VERSION 5.7 ;
  NOWIREEXTENSIONATPIN ON ;
  DIVIDERCHAR "/" ;
  BUSBITCHARS "[]" ;
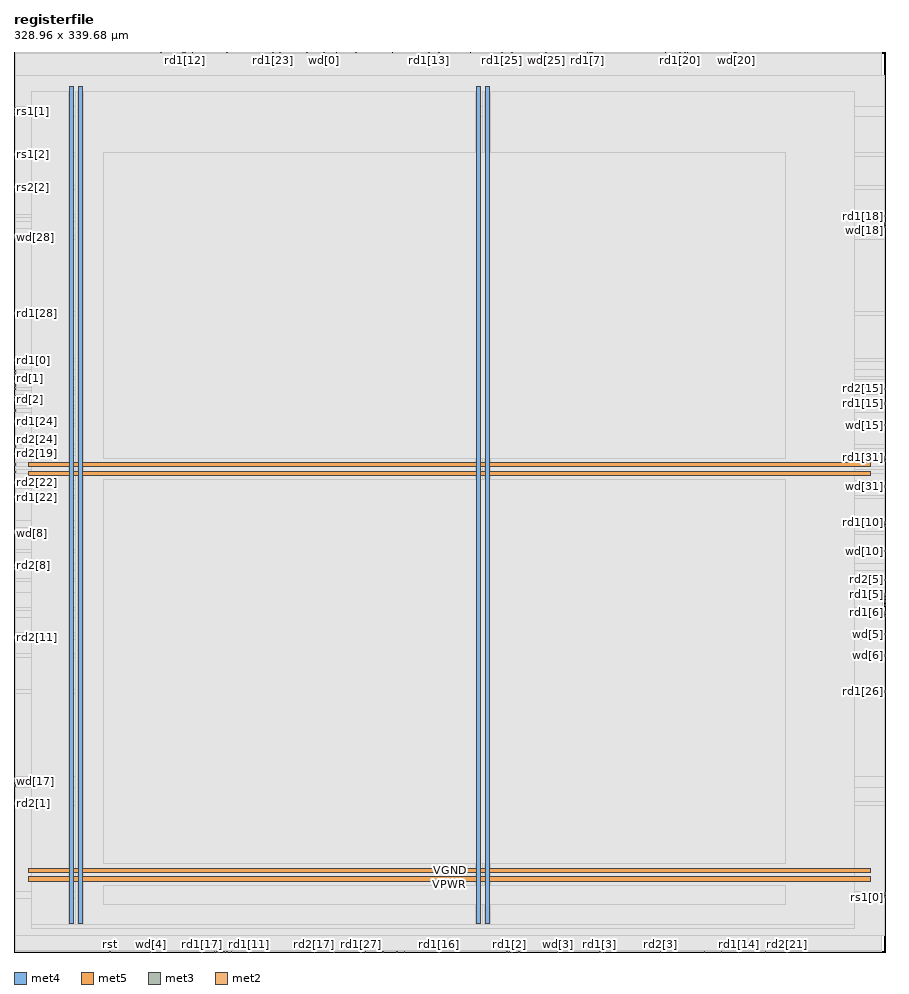
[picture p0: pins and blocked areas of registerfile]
MACRO registerfile
  CLASS BLOCK ;
  FOREIGN registerfile ;
  ORIGIN 0.000 0.000 ;
  SIZE 328.960 BY 339.680 ;
  PIN VGND
    DIRECTION INOUT ;
    USE GROUND ;
    PORT
      LAYER met4 ;
        RECT 24.340 10.640 25.940 326.640 ;
    END
    PORT
      LAYER met4 ;
        RECT 177.940 10.640 179.540 326.640 ;
    END
    PORT
      LAYER met5 ;
        RECT 5.520 30.030 323.380 31.630 ;
    END
    PORT
      LAYER met5 ;
        RECT 5.520 183.210 323.380 184.810 ;
    END
  END VGND
  PIN VPWR
    DIRECTION INOUT ;
    USE POWER ;
    PORT
      LAYER met4 ;
        RECT 21.040 10.640 22.640 326.640 ;
    END
    PORT
      LAYER met4 ;
        RECT 174.640 10.640 176.240 326.640 ;
    END
    PORT
      LAYER met5 ;
        RECT 5.520 26.730 323.380 28.330 ;
    END
    PORT
      LAYER met5 ;
        RECT 5.520 179.910 323.380 181.510 ;
    END
  END VPWR
  PIN clk
    DIRECTION INPUT ;
    USE SIGNAL ;
    ANTENNAGATEAREA 0.852000 ;
    PORT
      LAYER met3 ;
        RECT 0.000 318.280 0.600 318.880 ;
    END
  END clk
  PIN rd1[0]
    DIRECTION OUTPUT ;
    USE SIGNAL ;
    ANTENNADIFFAREA 0.383400 ;
    PORT
      LAYER met3 ;
        RECT 0.000 223.080 0.600 223.680 ;
    END
  END rd1[0]
  PIN rd1[10]
    DIRECTION OUTPUT ;
    USE SIGNAL ;
    ANTENNAGATEAREA 0.126000 ;
    ANTENNADIFFAREA 0.429000 ;
    PORT
      LAYER met3 ;
        RECT 328.360 161.880 328.960 162.480 ;
    END
  END rd1[10]
  PIN rd1[11]
    DIRECTION OUTPUT ;
    USE SIGNAL ;
    ANTENNAGATEAREA 0.126000 ;
    ANTENNADIFFAREA 0.429000 ;
    PORT
      LAYER met2 ;
        RECT 88.410 0.000 88.690 0.280 ;
    END
  END rd1[11]
  PIN rd1[12]
    DIRECTION OUTPUT ;
    USE SIGNAL ;
    ANTENNADIFFAREA 0.383400 ;
    PORT
      LAYER met2 ;
        RECT 64.490 339.400 64.770 339.680 ;
    END
  END rd1[12]
  PIN rd1[13]
    DIRECTION OUTPUT ;
    USE SIGNAL ;
    ANTENNADIFFAREA 0.429000 ;
    PORT
      LAYER met2 ;
        RECT 156.490 339.400 156.770 339.680 ;
    END
  END rd1[13]
  PIN rd1[14]
    DIRECTION OUTPUT ;
    USE SIGNAL ;
    ANTENNADIFFAREA 0.383400 ;
    PORT
      LAYER met2 ;
        RECT 273.330 0.000 273.610 0.280 ;
    END
  END rd1[14]
  PIN rd1[15]
    DIRECTION OUTPUT ;
    USE SIGNAL ;
    ANTENNAGATEAREA 0.126000 ;
    ANTENNADIFFAREA 0.429000 ;
    PORT
      LAYER met3 ;
        RECT 328.360 206.760 328.960 207.360 ;
    END
  END rd1[15]
  PIN rd1[16]
    DIRECTION OUTPUT ;
    USE SIGNAL ;
    ANTENNAGATEAREA 0.126000 ;
    ANTENNADIFFAREA 0.429000 ;
    PORT
      LAYER met2 ;
        RECT 160.170 0.000 160.450 0.280 ;
    END
  END rd1[16]
  PIN rd1[17]
    DIRECTION OUTPUT ;
    USE SIGNAL ;
    ANTENNAGATEAREA 0.126000 ;
    ANTENNADIFFAREA 0.429000 ;
    PORT
      LAYER met2 ;
        RECT 70.930 0.000 71.210 0.280 ;
    END
  END rd1[17]
  PIN rd1[18]
    DIRECTION OUTPUT ;
    USE SIGNAL ;
    ANTENNADIFFAREA 0.383400 ;
    PORT
      LAYER met3 ;
        RECT 328.360 277.480 328.960 278.080 ;
    END
  END rd1[18]
  PIN rd1[19]
    DIRECTION OUTPUT ;
    USE SIGNAL ;
    ANTENNADIFFAREA 0.383400 ;
    PORT
      LAYER met3 ;
        RECT 0.000 180.920 0.600 181.520 ;
    END
  END rd1[19]
  PIN rd1[1]
    DIRECTION OUTPUT ;
    USE SIGNAL ;
    ANTENNAGATEAREA 0.126000 ;
    ANTENNADIFFAREA 0.429000 ;
    PORT
      LAYER met2 ;
        RECT 76.450 0.000 76.730 0.280 ;
    END
  END rd1[1]
  PIN rd1[20]
    DIRECTION OUTPUT ;
    USE SIGNAL ;
    ANTENNADIFFAREA 0.383400 ;
    PORT
      LAYER met2 ;
        RECT 251.250 339.400 251.530 339.680 ;
    END
  END rd1[20]
  PIN rd1[21]
    DIRECTION OUTPUT ;
    USE SIGNAL ;
    ANTENNADIFFAREA 0.383400 ;
    PORT
      LAYER met2 ;
        RECT 283.450 0.000 283.730 0.280 ;
    END
  END rd1[21]
  PIN rd1[22]
    DIRECTION OUTPUT ;
    USE SIGNAL ;
    ANTENNADIFFAREA 0.702900 ;
    PORT
      LAYER met3 ;
        RECT 0.000 171.400 0.600 172.000 ;
    END
  END rd1[22]
  PIN rd1[23]
    DIRECTION OUTPUT ;
    USE SIGNAL ;
    ANTENNADIFFAREA 0.383400 ;
    PORT
      LAYER met2 ;
        RECT 97.610 339.400 97.890 339.680 ;
    END
  END rd1[23]
  PIN rd1[24]
    DIRECTION OUTPUT ;
    USE SIGNAL ;
    ANTENNADIFFAREA 0.383400 ;
    PORT
      LAYER met3 ;
        RECT 0.000 199.960 0.600 200.560 ;
    END
  END rd1[24]
  PIN rd1[25]
    DIRECTION OUTPUT ;
    USE SIGNAL ;
    ANTENNADIFFAREA 0.795200 ;
    PORT
      LAYER met2 ;
        RECT 184.090 339.400 184.370 339.680 ;
    END
  END rd1[25]
  PIN rd1[26]
    DIRECTION OUTPUT ;
    USE SIGNAL ;
    ANTENNAGATEAREA 0.126000 ;
    ANTENNADIFFAREA 0.429000 ;
    PORT
      LAYER met3 ;
        RECT 328.360 97.960 328.960 98.560 ;
    END
  END rd1[26]
  PIN rd1[27]
    DIRECTION OUTPUT ;
    USE SIGNAL ;
    ANTENNAGATEAREA 0.126000 ;
    ANTENNADIFFAREA 0.429000 ;
    PORT
      LAYER met2 ;
        RECT 130.730 0.000 131.010 0.280 ;
    END
  END rd1[27]
  PIN rd1[28]
    DIRECTION OUTPUT ;
    USE SIGNAL ;
    ANTENNADIFFAREA 0.383400 ;
    PORT
      LAYER met3 ;
        RECT 0.000 240.760 0.600 241.360 ;
    END
  END rd1[28]
  PIN rd1[29]
    DIRECTION OUTPUT ;
    USE SIGNAL ;
    ANTENNAGATEAREA 0.126000 ;
    ANTENNADIFFAREA 0.429000 ;
    PORT
      LAYER met2 ;
        RECT 144.530 0.000 144.810 0.280 ;
    END
  END rd1[29]
  PIN rd1[2]
    DIRECTION OUTPUT ;
    USE SIGNAL ;
    ANTENNADIFFAREA 0.891000 ;
    PORT
      LAYER met2 ;
        RECT 186.850 0.000 187.130 0.280 ;
    END
  END rd1[2]
  PIN rd1[30]
    DIRECTION OUTPUT ;
    USE SIGNAL ;
    ANTENNADIFFAREA 0.383400 ;
    PORT
      LAYER met2 ;
        RECT 128.890 339.400 129.170 339.680 ;
    END
  END rd1[30]
  PIN rd1[31]
    DIRECTION OUTPUT ;
    USE SIGNAL ;
    ANTENNAGATEAREA 0.126000 ;
    ANTENNADIFFAREA 0.429000 ;
    PORT
      LAYER met3 ;
        RECT 328.360 186.360 328.960 186.960 ;
    END
  END rd1[31]
  PIN rd1[3]
    DIRECTION OUTPUT ;
    USE SIGNAL ;
    ANTENNADIFFAREA 0.383400 ;
    PORT
      LAYER met2 ;
        RECT 220.890 0.000 221.170 0.280 ;
    END
  END rd1[3]
  PIN rd1[4]
    DIRECTION OUTPUT ;
    USE SIGNAL ;
    ANTENNADIFFAREA 0.795200 ;
    PORT
      LAYER met2 ;
        RECT 79.210 0.000 79.490 0.280 ;
    END
  END rd1[4]
  PIN rd1[5]
    DIRECTION OUTPUT ;
    USE SIGNAL ;
    ANTENNADIFFAREA 0.429000 ;
    PORT
      LAYER met3 ;
        RECT 328.360 134.680 328.960 135.280 ;
    END
  END rd1[5]
  PIN rd1[6]
    DIRECTION OUTPUT ;
    USE SIGNAL ;
    ANTENNADIFFAREA 0.383400 ;
    PORT
      LAYER met3 ;
        RECT 328.360 127.880 328.960 128.480 ;
    END
  END rd1[6]
  PIN rd1[7]
    DIRECTION OUTPUT ;
    USE SIGNAL ;
    ANTENNADIFFAREA 0.383400 ;
    PORT
      LAYER met2 ;
        RECT 216.290 339.400 216.570 339.680 ;
    END
  END rd1[7]
  PIN rd1[8]
    DIRECTION OUTPUT ;
    USE SIGNAL ;
    ANTENNAGATEAREA 0.126000 ;
    ANTENNADIFFAREA 0.429000 ;
    PORT
      LAYER met3 ;
        RECT 0.000 144.200 0.600 144.800 ;
    END
  END rd1[8]
  PIN rd1[9]
    DIRECTION OUTPUT ;
    USE SIGNAL ;
    ANTENNADIFFAREA 0.383400 ;
    PORT
      LAYER met2 ;
        RECT 253.090 339.400 253.370 339.680 ;
    END
  END rd1[9]
  PIN rd2[0]
    DIRECTION OUTPUT ;
    USE SIGNAL ;
    ANTENNADIFFAREA 0.383400 ;
    PORT
      LAYER met2 ;
        RECT 67.250 339.400 67.530 339.680 ;
    END
  END rd2[0]
  PIN rd2[10]
    DIRECTION OUTPUT ;
    USE SIGNAL ;
    ANTENNADIFFAREA 0.383400 ;
    PORT
      LAYER met3 ;
        RECT 328.360 160.520 328.960 161.120 ;
    END
  END rd2[10]
  PIN rd2[11]
    DIRECTION OUTPUT ;
    USE SIGNAL ;
    ANTENNADIFFAREA 0.383400 ;
    PORT
      LAYER met3 ;
        RECT 0.000 118.360 0.600 118.960 ;
    END
  END rd2[11]
  PIN rd2[12]
    DIRECTION OUTPUT ;
    USE SIGNAL ;
    ANTENNADIFFAREA 0.383400 ;
    PORT
      LAYER met2 ;
        RECT 55.290 339.400 55.570 339.680 ;
    END
  END rd2[12]
  PIN rd2[13]
    DIRECTION OUTPUT ;
    USE SIGNAL ;
    ANTENNAGATEAREA 0.126000 ;
    ANTENNADIFFAREA 0.429000 ;
    PORT
      LAYER met2 ;
        RECT 160.170 339.400 160.450 339.680 ;
    END
  END rd2[13]
  PIN rd2[14]
    DIRECTION OUTPUT ;
    USE SIGNAL ;
    ANTENNADIFFAREA 0.383400 ;
    PORT
      LAYER met2 ;
        RECT 266.890 0.000 267.170 0.280 ;
    END
  END rd2[14]
  PIN rd2[15]
    DIRECTION OUTPUT ;
    USE SIGNAL ;
    ANTENNAGATEAREA 0.126000 ;
    ANTENNADIFFAREA 0.429000 ;
    PORT
      LAYER met3 ;
        RECT 328.360 212.200 328.960 212.800 ;
    END
  END rd2[15]
  PIN rd2[16]
    DIRECTION OUTPUT ;
    USE SIGNAL ;
    ANTENNAGATEAREA 0.126000 ;
    ANTENNADIFFAREA 0.429000 ;
    PORT
      LAYER met3 ;
        RECT 328.360 131.960 328.960 132.560 ;
    END
  END rd2[16]
  PIN rd2[17]
    DIRECTION OUTPUT ;
    USE SIGNAL ;
    ANTENNADIFFAREA 0.445500 ;
    PORT
      LAYER met2 ;
        RECT 113.250 0.000 113.530 0.280 ;
    END
  END rd2[17]
  PIN rd2[18]
    DIRECTION OUTPUT ;
    USE SIGNAL ;
    ANTENNADIFFAREA 0.795200 ;
    PORT
      LAYER met2 ;
        RECT 218.130 339.400 218.410 339.680 ;
    END
  END rd2[18]
  PIN rd2[19]
    DIRECTION OUTPUT ;
    USE SIGNAL ;
    ANTENNADIFFAREA 0.383400 ;
    PORT
      LAYER met3 ;
        RECT 0.000 187.720 0.600 188.320 ;
    END
  END rd2[19]
  PIN rd2[1]
    DIRECTION OUTPUT ;
    USE SIGNAL ;
    ANTENNADIFFAREA 0.383400 ;
    PORT
      LAYER met3 ;
        RECT 0.000 55.800 0.600 56.400 ;
    END
  END rd2[1]
  PIN rd2[20]
    DIRECTION OUTPUT ;
    USE SIGNAL ;
    ANTENNAGATEAREA 0.126000 ;
    ANTENNADIFFAREA 0.429000 ;
    PORT
      LAYER met2 ;
        RECT 245.730 339.400 246.010 339.680 ;
    END
  END rd2[20]
  PIN rd2[21]
    DIRECTION OUTPUT ;
    USE SIGNAL ;
    ANTENNAGATEAREA 0.126000 ;
    ANTENNADIFFAREA 0.429000 ;
    PORT
      LAYER met2 ;
        RECT 291.730 0.000 292.010 0.280 ;
    END
  END rd2[21]
  PIN rd2[22]
    DIRECTION OUTPUT ;
    USE SIGNAL ;
    ANTENNADIFFAREA 0.383400 ;
    PORT
      LAYER met3 ;
        RECT 0.000 176.840 0.600 177.440 ;
    END
  END rd2[22]
  PIN rd2[23]
    DIRECTION OUTPUT ;
    USE SIGNAL ;
    ANTENNADIFFAREA 0.383400 ;
    PORT
      LAYER met2 ;
        RECT 100.370 339.400 100.650 339.680 ;
    END
  END rd2[23]
  PIN rd2[24]
    DIRECTION OUTPUT ;
    USE SIGNAL ;
    ANTENNADIFFAREA 0.383400 ;
    PORT
      LAYER met3 ;
        RECT 0.000 190.440 0.600 191.040 ;
    END
  END rd2[24]
  PIN rd2[25]
    DIRECTION OUTPUT ;
    USE SIGNAL ;
    ANTENNADIFFAREA 0.383400 ;
    PORT
      LAYER met2 ;
        RECT 187.770 339.400 188.050 339.680 ;
    END
  END rd2[25]
  PIN rd2[26]
    DIRECTION OUTPUT ;
    USE SIGNAL ;
    ANTENNAGATEAREA 0.126000 ;
    ANTENNADIFFAREA 0.429000 ;
    PORT
      LAYER met2 ;
        RECT 260.450 0.000 260.730 0.280 ;
    END
  END rd2[26]
  PIN rd2[27]
    DIRECTION OUTPUT ;
    USE SIGNAL ;
    ANTENNADIFFAREA 1.336500 ;
    PORT
      LAYER met2 ;
        RECT 132.570 0.000 132.850 0.280 ;
    END
  END rd2[27]
  PIN rd2[28]
    DIRECTION OUTPUT ;
    USE SIGNAL ;
    ANTENNADIFFAREA 0.445500 ;
    PORT
      LAYER met2 ;
        RECT 80.130 339.400 80.410 339.680 ;
    END
  END rd2[28]
  PIN rd2[29]
    DIRECTION OUTPUT ;
    USE SIGNAL ;
    ANTENNADIFFAREA 0.429000 ;
    PORT
      LAYER met2 ;
        RECT 147.290 0.000 147.570 0.280 ;
    END
  END rd2[29]
  PIN rd2[2]
    DIRECTION OUTPUT ;
    USE SIGNAL ;
    ANTENNAGATEAREA 0.126000 ;
    ANTENNADIFFAREA 0.429000 ;
    PORT
      LAYER met2 ;
        RECT 185.930 0.000 186.210 0.280 ;
    END
  END rd2[2]
  PIN rd2[30]
    DIRECTION OUTPUT ;
    USE SIGNAL ;
    ANTENNADIFFAREA 0.383400 ;
    PORT
      LAYER met2 ;
        RECT 63.570 339.400 63.850 339.680 ;
    END
  END rd2[30]
  PIN rd2[31]
    DIRECTION OUTPUT ;
    USE SIGNAL ;
    ANTENNAGATEAREA 0.126000 ;
    ANTENNADIFFAREA 0.429000 ;
    PORT
      LAYER met3 ;
        RECT 328.360 185.000 328.960 185.600 ;
    END
  END rd2[31]
  PIN rd2[3]
    DIRECTION OUTPUT ;
    USE SIGNAL ;
    ANTENNADIFFAREA 0.795200 ;
    PORT
      LAYER met2 ;
        RECT 243.890 0.000 244.170 0.280 ;
    END
  END rd2[3]
  PIN rd2[4]
    DIRECTION OUTPUT ;
    USE SIGNAL ;
    ANTENNADIFFAREA 1.336500 ;
    PORT
      LAYER met2 ;
        RECT 81.970 0.000 82.250 0.280 ;
    END
  END rd2[4]
  PIN rd2[5]
    DIRECTION OUTPUT ;
    USE SIGNAL ;
    ANTENNADIFFAREA 0.383400 ;
    PORT
      LAYER met3 ;
        RECT 328.360 140.120 328.960 140.720 ;
    END
  END rd2[5]
  PIN rd2[6]
    DIRECTION OUTPUT ;
    USE SIGNAL ;
    ANTENNAGATEAREA 0.126000 ;
    ANTENNADIFFAREA 0.429000 ;
    PORT
      LAYER met3 ;
        RECT 328.360 133.320 328.960 133.920 ;
    END
  END rd2[6]
  PIN rd2[7]
    DIRECTION OUTPUT ;
    USE SIGNAL ;
    ANTENNADIFFAREA 0.383400 ;
    PORT
      LAYER met2 ;
        RECT 217.210 339.400 217.490 339.680 ;
    END
  END rd2[7]
  PIN rd2[8]
    DIRECTION OUTPUT ;
    USE SIGNAL ;
    ANTENNADIFFAREA 0.383400 ;
    PORT
      LAYER met3 ;
        RECT 0.000 145.560 0.600 146.160 ;
    END
  END rd2[8]
  PIN rd2[9]
    DIRECTION OUTPUT ;
    USE SIGNAL ;
    ANTENNADIFFAREA 0.383400 ;
    PORT
      LAYER met2 ;
        RECT 254.010 339.400 254.290 339.680 ;
    END
  END rd2[9]
  PIN rd[0]
    DIRECTION INPUT ;
    USE SIGNAL ;
    ANTENNAGATEAREA 0.213000 ;
    PORT
      LAYER met3 ;
        RECT 0.000 217.640 0.600 218.240 ;
    END
  END rd[0]
  PIN rd[1]
    DIRECTION INPUT ;
    USE SIGNAL ;
    ANTENNAGATEAREA 0.213000 ;
    PORT
      LAYER met3 ;
        RECT 0.000 219.000 0.600 219.600 ;
    END
  END rd[1]
  PIN rd[2]
    DIRECTION INPUT ;
    USE SIGNAL ;
    ANTENNAGATEAREA 0.213000 ;
    PORT
      LAYER met3 ;
        RECT 0.000 208.120 0.600 208.720 ;
    END
  END rd[2]
  PIN rd[3]
    DIRECTION INPUT ;
    USE SIGNAL ;
    ANTENNAGATEAREA 0.213000 ;
    PORT
      LAYER met3 ;
        RECT 0.000 214.920 0.600 215.520 ;
    END
  END rd[3]
  PIN rd[4]
    DIRECTION INPUT ;
    USE SIGNAL ;
    ANTENNAGATEAREA 0.213000 ;
    PORT
      LAYER met3 ;
        RECT 0.000 213.560 0.600 214.160 ;
    END
  END rd[4]
  PIN rs1[0]
    DIRECTION INPUT ;
    USE SIGNAL ;
    ANTENNAGATEAREA 0.213000 ;
    PORT
      LAYER met3 ;
        RECT 328.360 20.440 328.960 21.040 ;
    END
  END rs1[0]
  PIN rs1[1]
    DIRECTION INPUT ;
    USE SIGNAL ;
    ANTENNAGATEAREA 0.159000 ;
    PORT
      LAYER met3 ;
        RECT 0.000 316.920 0.600 317.520 ;
    END
  END rs1[1]
  PIN rs1[2]
    DIRECTION INPUT ;
    USE SIGNAL ;
    ANTENNAGATEAREA 0.213000 ;
    PORT
      LAYER met3 ;
        RECT 0.000 300.600 0.600 301.200 ;
    END
  END rs1[2]
  PIN rs1[3]
    DIRECTION INPUT ;
    USE SIGNAL ;
    ANTENNAGATEAREA 0.213000 ;
    PORT
      LAYER met2 ;
        RECT 80.130 0.000 80.410 0.280 ;
    END
  END rs1[3]
  PIN rs1[4]
    DIRECTION INPUT ;
    USE SIGNAL ;
    ANTENNAGATEAREA 0.213000 ;
    PORT
      LAYER met2 ;
        RECT 75.530 0.000 75.810 0.280 ;
    END
  END rs1[4]
  PIN rs2[0]
    DIRECTION INPUT ;
    USE SIGNAL ;
    ANTENNAGATEAREA 0.213000 ;
    PORT
      LAYER met3 ;
        RECT 328.360 21.800 328.960 22.400 ;
    END
  END rs2[0]
  PIN rs2[1]
    DIRECTION INPUT ;
    USE SIGNAL ;
    ANTENNAGATEAREA 0.213000 ;
    PORT
      LAYER met3 ;
        RECT 0.000 315.560 0.600 316.160 ;
    END
  END rs2[1]
  PIN rs2[2]
    DIRECTION INPUT ;
    USE SIGNAL ;
    ANTENNAGATEAREA 0.213000 ;
    PORT
      LAYER met3 ;
        RECT 0.000 288.360 0.600 288.960 ;
    END
  END rs2[2]
  PIN rs2[3]
    DIRECTION INPUT ;
    USE SIGNAL ;
    ANTENNAGATEAREA 0.213000 ;
    PORT
      LAYER met3 ;
        RECT 328.360 126.520 328.960 127.120 ;
    END
  END rs2[3]
  PIN rs2[4]
    DIRECTION INPUT ;
    USE SIGNAL ;
    ANTENNAGATEAREA 0.213000 ;
    PORT
      LAYER met3 ;
        RECT 328.360 130.600 328.960 131.200 ;
    END
  END rs2[4]
  PIN rst
    DIRECTION INPUT ;
    USE SIGNAL ;
    ANTENNAGATEAREA 0.213000 ;
    PORT
      LAYER met2 ;
        RECT 35.970 0.000 36.250 0.280 ;
    END
  END rst
  PIN wd[0]
    DIRECTION INPUT ;
    USE SIGNAL ;
    ANTENNAGATEAREA 0.213000 ;
    PORT
      LAYER met2 ;
        RECT 116.930 339.400 117.210 339.680 ;
    END
  END wd[0]
  PIN wd[10]
    DIRECTION INPUT ;
    USE SIGNAL ;
    ANTENNAGATEAREA 0.213000 ;
    PORT
      LAYER met3 ;
        RECT 328.360 151.000 328.960 151.600 ;
    END
  END wd[10]
  PIN wd[11]
    DIRECTION INPUT ;
    USE SIGNAL ;
    ANTENNAGATEAREA 0.213000 ;
    PORT
      LAYER met3 ;
        RECT 0.000 65.320 0.600 65.920 ;
    END
  END wd[11]
  PIN wd[12]
    DIRECTION INPUT ;
    USE SIGNAL ;
    ANTENNAGATEAREA 0.213000 ;
    PORT
      LAYER met2 ;
        RECT 121.530 339.400 121.810 339.680 ;
    END
  END wd[12]
  PIN wd[13]
    DIRECTION INPUT ;
    USE SIGNAL ;
    ANTENNAGATEAREA 0.213000 ;
    PORT
      LAYER met2 ;
        RECT 172.130 339.400 172.410 339.680 ;
    END
  END wd[13]
  PIN wd[14]
    DIRECTION INPUT ;
    USE SIGNAL ;
    ANTENNAGATEAREA 0.213000 ;
    PORT
      LAYER met2 ;
        RECT 221.810 0.000 222.090 0.280 ;
    END
  END wd[14]
  PIN wd[15]
    DIRECTION INPUT ;
    USE SIGNAL ;
    ANTENNAGATEAREA 0.213000 ;
    PORT
      LAYER met3 ;
        RECT 328.360 198.600 328.960 199.200 ;
    END
  END wd[15]
  PIN wd[16]
    DIRECTION INPUT ;
    USE SIGNAL ;
    ANTENNAGATEAREA 0.213000 ;
    PORT
      LAYER met2 ;
        RECT 139.010 0.000 139.290 0.280 ;
    END
  END wd[16]
  PIN wd[17]
    DIRECTION INPUT ;
    USE SIGNAL ;
    ANTENNAGATEAREA 0.213000 ;
    PORT
      LAYER met3 ;
        RECT 0.000 63.960 0.600 64.560 ;
    END
  END wd[17]
  PIN wd[18]
    DIRECTION INPUT ;
    USE SIGNAL ;
    ANTENNAGATEAREA 0.213000 ;
    PORT
      LAYER met3 ;
        RECT 328.360 274.760 328.960 275.360 ;
    END
  END wd[18]
  PIN wd[19]
    DIRECTION INPUT ;
    USE SIGNAL ;
    ANTENNAGATEAREA 0.213000 ;
    PORT
      LAYER met3 ;
        RECT 0.000 204.040 0.600 204.640 ;
    END
  END wd[19]
  PIN wd[1]
    DIRECTION INPUT ;
    USE SIGNAL ;
    ANTENNAGATEAREA 0.213000 ;
    PORT
      LAYER met3 ;
        RECT 0.000 62.600 0.600 63.200 ;
    END
  END wd[1]
  PIN wd[20]
    DIRECTION INPUT ;
    USE SIGNAL ;
    ANTENNAGATEAREA 0.213000 ;
    PORT
      LAYER met2 ;
        RECT 272.410 339.400 272.690 339.680 ;
    END
  END wd[20]
  PIN wd[21]
    DIRECTION INPUT ;
    USE SIGNAL ;
    ANTENNAGATEAREA 0.213000 ;
    PORT
      LAYER met2 ;
        RECT 222.730 0.000 223.010 0.280 ;
    END
  END wd[21]
  PIN wd[22]
    DIRECTION INPUT ;
    USE SIGNAL ;
    ANTENNAGATEAREA 0.213000 ;
    PORT
      LAYER met3 ;
        RECT 0.000 183.640 0.600 184.240 ;
    END
  END wd[22]
  PIN wd[23]
    DIRECTION INPUT ;
    USE SIGNAL ;
    ANTENNAGATEAREA 0.213000 ;
    PORT
      LAYER met2 ;
        RECT 110.490 339.400 110.770 339.680 ;
    END
  END wd[23]
  PIN wd[24]
    DIRECTION INPUT ;
    USE SIGNAL ;
    ANTENNAGATEAREA 0.213000 ;
    PORT
      LAYER met3 ;
        RECT 0.000 212.200 0.600 212.800 ;
    END
  END wd[24]
  PIN wd[25]
    DIRECTION INPUT ;
    USE SIGNAL ;
    ANTENNAGATEAREA 0.213000 ;
    PORT
      LAYER met2 ;
        RECT 200.650 339.400 200.930 339.680 ;
    END
  END wd[25]
  PIN wd[26]
    DIRECTION INPUT ;
    USE SIGNAL ;
    ANTENNAGATEAREA 0.213000 ;
    PORT
      LAYER met2 ;
        RECT 190.530 0.000 190.810 0.280 ;
    END
  END wd[26]
  PIN wd[27]
    DIRECTION INPUT ;
    USE SIGNAL ;
    ANTENNAGATEAREA 0.213000 ;
    PORT
      LAYER met2 ;
        RECT 77.370 0.000 77.650 0.280 ;
    END
  END wd[27]
  PIN wd[28]
    DIRECTION INPUT ;
    USE SIGNAL ;
    ANTENNAGATEAREA 0.213000 ;
    PORT
      LAYER met3 ;
        RECT 0.000 269.320 0.600 269.920 ;
    END
  END wd[28]
  PIN wd[29]
    DIRECTION INPUT ;
    USE SIGNAL ;
    ANTENNAGATEAREA 0.213000 ;
    PORT
      LAYER met2 ;
        RECT 120.610 0.000 120.890 0.280 ;
    END
  END wd[29]
  PIN wd[2]
    DIRECTION INPUT ;
    USE SIGNAL ;
    ANTENNAGATEAREA 0.213000 ;
    PORT
      LAYER met2 ;
        RECT 187.770 0.000 188.050 0.280 ;
    END
  END wd[2]
  PIN wd[30]
    DIRECTION INPUT ;
    USE SIGNAL ;
    ANTENNAGATEAREA 0.213000 ;
    PORT
      LAYER met2 ;
        RECT 142.690 339.400 142.970 339.680 ;
    END
  END wd[30]
  PIN wd[31]
    DIRECTION INPUT ;
    USE SIGNAL ;
    ANTENNAGATEAREA 0.213000 ;
    PORT
      LAYER met3 ;
        RECT 328.360 175.480 328.960 176.080 ;
    END
  END wd[31]
  PIN wd[3]
    DIRECTION INPUT ;
    USE SIGNAL ;
    ANTENNAGATEAREA 0.213000 ;
    PORT
      LAYER met2 ;
        RECT 205.250 0.000 205.530 0.280 ;
    END
  END wd[3]
  PIN wd[4]
    DIRECTION INPUT ;
    USE SIGNAL ;
    ANTENNAGATEAREA 0.213000 ;
    PORT
      LAYER met2 ;
        RECT 51.610 0.000 51.890 0.280 ;
    END
  END wd[4]
  PIN wd[5]
    DIRECTION INPUT ;
    USE SIGNAL ;
    ANTENNAGATEAREA 0.213000 ;
    PORT
      LAYER met3 ;
        RECT 328.360 119.720 328.960 120.320 ;
    END
  END wd[5]
  PIN wd[6]
    DIRECTION INPUT ;
    USE SIGNAL ;
    ANTENNAGATEAREA 0.213000 ;
    PORT
      LAYER met3 ;
        RECT 328.360 111.560 328.960 112.160 ;
    END
  END wd[6]
  PIN wd[7]
    DIRECTION INPUT ;
    USE SIGNAL ;
    ANTENNAGATEAREA 0.213000 ;
    PORT
      LAYER met3 ;
        RECT 328.360 273.400 328.960 274.000 ;
    END
  END wd[7]
  PIN wd[8]
    DIRECTION INPUT ;
    USE SIGNAL ;
    ANTENNAGATEAREA 0.213000 ;
    PORT
      LAYER met3 ;
        RECT 0.000 157.800 0.600 158.400 ;
    END
  END wd[8]
  PIN wd[9]
    DIRECTION INPUT ;
    USE SIGNAL ;
    ANTENNAGATEAREA 0.213000 ;
    PORT
      LAYER met2 ;
        RECT 271.490 339.400 271.770 339.680 ;
    END
  END wd[9]
  PIN we
    DIRECTION INPUT ;
    USE SIGNAL ;
    ANTENNAGATEAREA 0.213000 ;
    PORT
      LAYER met3 ;
        RECT 0.000 209.480 0.600 210.080 ;
    END
  END we
  OBS
      LAYER nwell ;
        RECT 5.330 10.795 323.570 326.485 ;
      LAYER li1 ;
        RECT 5.520 10.795 323.380 326.485 ;
      LAYER met1 ;
        RECT 0.990 4.120 327.450 328.400 ;
      LAYER met2 ;
        RECT 0.550 339.120 55.010 339.400 ;
        RECT 55.850 339.120 63.290 339.400 ;
        RECT 64.130 339.120 64.210 339.400 ;
        RECT 65.050 339.120 66.970 339.400 ;
        RECT 67.810 339.120 79.850 339.400 ;
        RECT 80.690 339.120 97.330 339.400 ;
        RECT 98.170 339.120 100.090 339.400 ;
        RECT 100.930 339.120 110.210 339.400 ;
        RECT 111.050 339.120 116.650 339.400 ;
        RECT 117.490 339.120 121.250 339.400 ;
        RECT 122.090 339.120 128.610 339.400 ;
        RECT 129.450 339.120 142.410 339.400 ;
        RECT 143.250 339.120 156.210 339.400 ;
        RECT 157.050 339.120 159.890 339.400 ;
        RECT 160.730 339.120 171.850 339.400 ;
        RECT 172.690 339.120 183.810 339.400 ;
        RECT 184.650 339.120 187.490 339.400 ;
        RECT 188.330 339.120 200.370 339.400 ;
        RECT 201.210 339.120 216.010 339.400 ;
        RECT 216.850 339.120 216.930 339.400 ;
        RECT 217.770 339.120 217.850 339.400 ;
        RECT 218.690 339.120 245.450 339.400 ;
        RECT 246.290 339.120 250.970 339.400 ;
        RECT 251.810 339.120 252.810 339.400 ;
        RECT 253.650 339.120 253.730 339.400 ;
        RECT 254.570 339.120 271.210 339.400 ;
        RECT 272.050 339.120 272.130 339.400 ;
        RECT 272.970 339.120 327.430 339.400 ;
        RECT 0.550 0.560 327.430 339.120 ;
        RECT 0.550 0.070 35.690 0.560 ;
        RECT 36.530 0.070 51.330 0.560 ;
        RECT 52.170 0.070 70.650 0.560 ;
        RECT 71.490 0.070 75.250 0.560 ;
        RECT 76.090 0.070 76.170 0.560 ;
        RECT 77.010 0.070 77.090 0.560 ;
        RECT 77.930 0.070 78.930 0.560 ;
        RECT 79.770 0.070 79.850 0.560 ;
        RECT 80.690 0.070 81.690 0.560 ;
        RECT 82.530 0.070 88.130 0.560 ;
        RECT 88.970 0.070 112.970 0.560 ;
        RECT 113.810 0.070 120.330 0.560 ;
        RECT 121.170 0.070 130.450 0.560 ;
        RECT 131.290 0.070 132.290 0.560 ;
        RECT 133.130 0.070 138.730 0.560 ;
        RECT 139.570 0.070 144.250 0.560 ;
        RECT 145.090 0.070 147.010 0.560 ;
        RECT 147.850 0.070 159.890 0.560 ;
        RECT 160.730 0.070 185.650 0.560 ;
        RECT 186.490 0.070 186.570 0.560 ;
        RECT 187.410 0.070 187.490 0.560 ;
        RECT 188.330 0.070 190.250 0.560 ;
        RECT 191.090 0.070 204.970 0.560 ;
        RECT 205.810 0.070 220.610 0.560 ;
        RECT 221.450 0.070 221.530 0.560 ;
        RECT 222.370 0.070 222.450 0.560 ;
        RECT 223.290 0.070 243.610 0.560 ;
        RECT 244.450 0.070 260.170 0.560 ;
        RECT 261.010 0.070 266.610 0.560 ;
        RECT 267.450 0.070 273.050 0.560 ;
        RECT 273.890 0.070 283.170 0.560 ;
        RECT 284.010 0.070 291.450 0.560 ;
        RECT 292.290 0.070 327.430 0.560 ;
      LAYER met3 ;
        RECT 0.525 319.280 328.360 330.985 ;
        RECT 1.000 315.160 328.360 319.280 ;
        RECT 0.525 301.600 328.360 315.160 ;
        RECT 1.000 300.200 328.360 301.600 ;
        RECT 0.525 289.360 328.360 300.200 ;
        RECT 1.000 287.960 328.360 289.360 ;
        RECT 0.525 278.480 328.360 287.960 ;
        RECT 0.525 277.080 327.960 278.480 ;
        RECT 0.525 275.760 328.360 277.080 ;
        RECT 0.525 273.000 327.960 275.760 ;
        RECT 0.525 270.320 328.360 273.000 ;
        RECT 1.000 268.920 328.360 270.320 ;
        RECT 0.525 241.760 328.360 268.920 ;
        RECT 1.000 240.360 328.360 241.760 ;
        RECT 0.525 224.080 328.360 240.360 ;
        RECT 1.000 222.680 328.360 224.080 ;
        RECT 0.525 220.000 328.360 222.680 ;
        RECT 1.000 217.240 328.360 220.000 ;
        RECT 0.525 215.920 328.360 217.240 ;
        RECT 1.000 213.200 328.360 215.920 ;
        RECT 1.000 211.800 327.960 213.200 ;
        RECT 0.525 210.480 328.360 211.800 ;
        RECT 1.000 207.760 328.360 210.480 ;
        RECT 1.000 207.720 327.960 207.760 ;
        RECT 0.525 206.360 327.960 207.720 ;
        RECT 0.525 205.040 328.360 206.360 ;
        RECT 1.000 203.640 328.360 205.040 ;
        RECT 0.525 200.960 328.360 203.640 ;
        RECT 1.000 199.600 328.360 200.960 ;
        RECT 1.000 199.560 327.960 199.600 ;
        RECT 0.525 198.200 327.960 199.560 ;
        RECT 0.525 191.440 328.360 198.200 ;
        RECT 1.000 190.040 328.360 191.440 ;
        RECT 0.525 188.720 328.360 190.040 ;
        RECT 1.000 187.360 328.360 188.720 ;
        RECT 1.000 187.320 327.960 187.360 ;
        RECT 0.525 184.640 327.960 187.320 ;
        RECT 1.000 184.600 327.960 184.640 ;
        RECT 1.000 183.240 328.360 184.600 ;
        RECT 0.525 181.920 328.360 183.240 ;
        RECT 1.000 180.520 328.360 181.920 ;
        RECT 0.525 177.840 328.360 180.520 ;
        RECT 1.000 176.480 328.360 177.840 ;
        RECT 1.000 176.440 327.960 176.480 ;
        RECT 0.525 175.080 327.960 176.440 ;
        RECT 0.525 172.400 328.360 175.080 ;
        RECT 1.000 171.000 328.360 172.400 ;
        RECT 0.525 162.880 328.360 171.000 ;
        RECT 0.525 160.120 327.960 162.880 ;
        RECT 0.525 158.800 328.360 160.120 ;
        RECT 1.000 157.400 328.360 158.800 ;
        RECT 0.525 152.000 328.360 157.400 ;
        RECT 0.525 150.600 327.960 152.000 ;
        RECT 0.525 146.560 328.360 150.600 ;
        RECT 1.000 143.800 328.360 146.560 ;
        RECT 0.525 141.120 328.360 143.800 ;
        RECT 0.525 139.720 327.960 141.120 ;
        RECT 0.525 135.680 328.360 139.720 ;
        RECT 0.525 130.200 327.960 135.680 ;
        RECT 0.525 128.880 328.360 130.200 ;
        RECT 0.525 126.120 327.960 128.880 ;
        RECT 0.525 120.720 328.360 126.120 ;
        RECT 0.525 119.360 327.960 120.720 ;
        RECT 1.000 119.320 327.960 119.360 ;
        RECT 1.000 117.960 328.360 119.320 ;
        RECT 0.525 112.560 328.360 117.960 ;
        RECT 0.525 111.160 327.960 112.560 ;
        RECT 0.525 98.960 328.360 111.160 ;
        RECT 0.525 97.560 327.960 98.960 ;
        RECT 0.525 66.320 328.360 97.560 ;
        RECT 1.000 62.200 328.360 66.320 ;
        RECT 0.525 56.800 328.360 62.200 ;
        RECT 1.000 55.400 328.360 56.800 ;
        RECT 0.525 22.800 328.360 55.400 ;
        RECT 0.525 20.040 327.960 22.800 ;
        RECT 0.525 6.295 328.360 20.040 ;
      LAYER met4 ;
        RECT 6.735 10.240 20.640 324.865 ;
        RECT 23.040 10.240 23.940 324.865 ;
        RECT 26.340 10.240 174.240 324.865 ;
        RECT 176.640 10.240 177.540 324.865 ;
        RECT 179.940 10.240 317.105 324.865 ;
        RECT 6.735 9.015 317.105 10.240 ;
      LAYER met5 ;
        RECT 33.700 186.410 291.060 301.700 ;
        RECT 33.700 33.230 291.060 178.310 ;
        RECT 33.700 17.900 291.060 25.130 ;
  END
END registerfile
END LIBRARY

